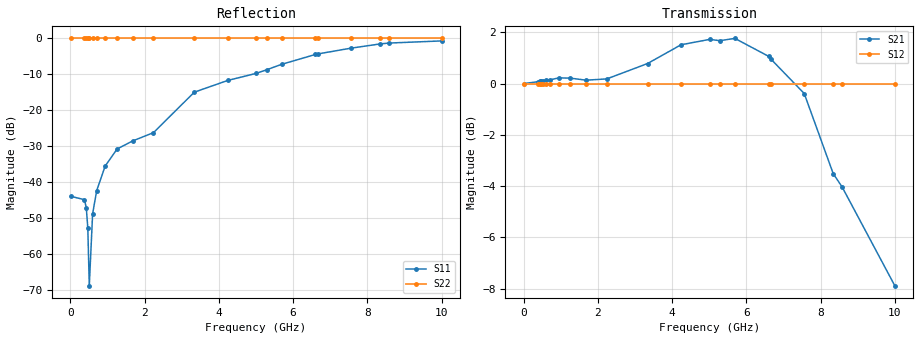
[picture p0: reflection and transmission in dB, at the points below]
! Texas Instruments, Inc.
! ADC12DJ5200RF - CH A S-Parameters (DES Mode, Fs = 10.4 GSPS, 0 degC case, 15 degC juntion)
! Port 1 represents the 100-ohm differenal input, Port 2 the digital output
! freq  dbS11  angS11  dbS21 angS21 dbS12 angS12 dbS22 angS22
# HZ S DB R 100
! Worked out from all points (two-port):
!   1000 points, 10 MHz to 10 GHz, reference 100 ohm
!   highest |S21| = 1.76 dB at 5.69 GHz (marker M1); lowest = -7.9 dB at 10 GHz (marker M2)
!   |S21| within 3 dB of the highest: start of sweep to 7.814 GHz
!   lowest |S11| = -68.9 dB at 510 MHz (marker M3), VSWR 1.00, Z = 100 - j0.0713 ohm
!   |S11| at or under -10 dB: start of sweep to 4.932 GHz
!   |S22| runs from 0.0 to 0.0 dB; largest |S21 - S12| = 0.83
!   S11 on the Smith chart (normalised r, x): 10 MHz: 1.01, -0.00; 5.29 GHz: 0.47, +0.10; 6.6 GHz: 0.55, +1.01; 7.56 GHz: 3.35, +3.13; 8.58 GHz: 0.75, -2.91; 10 GHz: 0.09, -1.12
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1e7  -43.98 -7.6  0.00 0.0  0.00 0.0  0.00 0.0
3.8e8  -44.92 -10.5  0.07 0.3  0.00 0.0  0.00 0.0
4.3e8  -47.24 -0.5  0.08 0.3  0.00 0.0  0.00 0.0
4.7e8  -52.81 6.8  0.08 0.3  0.00 0.0  0.00 0.0
5.1e8  -68.87 -81.6  0.10 0.3  0.00 0.0  0.00 0.0
6e8  -48.82 -136.8  0.12 0.3  0.00 0.0  0.00 0.0
7.1e8  -42.37 -157.4  0.14 0.3  0.00 0.0  0.00 0.0
9.4e8  -35.52 -169.1  0.22 -0.0  0.00 0.0  0.00 0.0
1.26e9  -30.80 -171.7  0.21 -0.7  0.00 0.0  0.00 0.0
1.68e9  -28.56 -163.4  0.13 -0.8  0.00 0.0  0.00 0.0
2.24e9  -26.25 -119.8  0.18 -0.5  0.00 0.0  0.00 0.0
3.34e9  -14.98 -96.9  0.78 -0.1  0.00 0.0  0.00 0.0
4.24e9  -11.72 -125.9  1.51 -3.8  0.00 0.0  0.00 0.0
5.01e9  -9.74 -174.4  1.72 -11.2  0.00 0.0  0.00 0.0
5.29e9  -8.74 165.9  1.67 -13.0  0.00 0.0  0.00 0.0
5.69e9  -7.24 139.3  1.76 -17.2  0.00 0.0  0.00 0.0
6.6e9  -4.49 81.1  1.06 -30.9  0.00 0.0  0.00 0.0
6.67e9  -4.33 76.5  0.94 -31.8  0.00 0.0  0.00 0.0
7.56e9  -2.73 17.4  -0.39 -45.3  0.00 0.0  0.00 0.0
8.34e9  -1.56 -25.8  -3.51 -50.6  0.00 0.0  0.00 0.0
8.58e9  -1.31 -35.9  -4.03 -48.4  0.00 0.0  0.00 0.0
1e10  -0.71 -83.2  -7.88 -53.4  0.00 0.0  0.00 0.0
